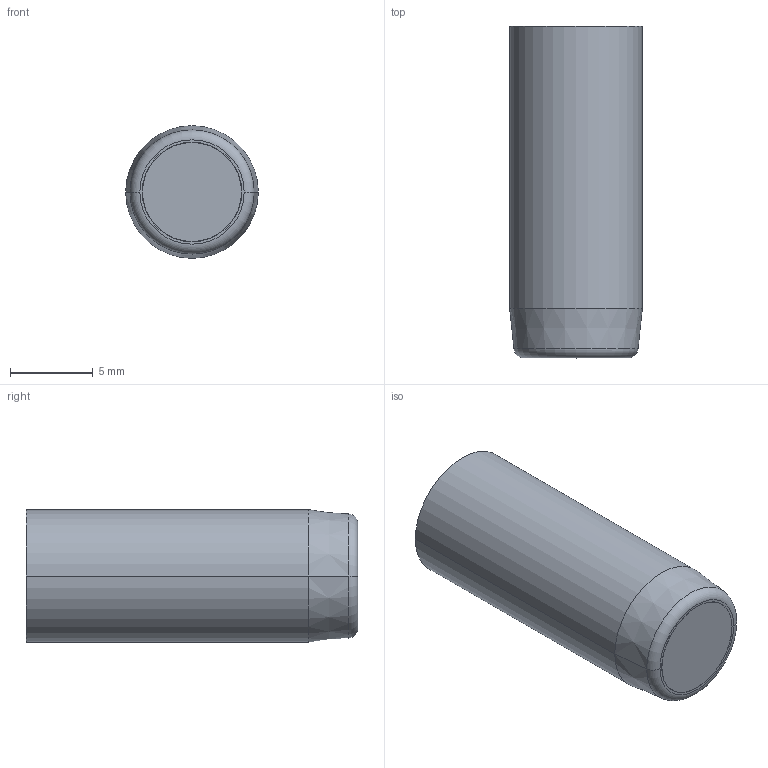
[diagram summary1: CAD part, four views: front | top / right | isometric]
STEP (ISO 10303-21) file: header records copied from the file, then geometry measured from it (millimetres).
FILE_DESCRIPTION (( 'STEP AP214' ), '1' );
FILE_NAME ('FA 084712-20.STEP', '2013-10-01T09:20:54', ( '' ), ( '' ), 'SwSTEP 2.0', 'SolidWorks 2011', '' );
FILE_SCHEMA (( 'AUTOMOTIVE_DESIGN' ));
Length unit declared in the file: millimetre
Products named in the file (6): 9FA 084712; FA 084700-2 comprimido; FA 084712-20; IA 471720; FA 084700-3; FA 084700-1
Assembly tree (5 placements, depth 2):
  FA 084712-20
    FA 084700-2 comprimido
    FA 084700-3
    FA 084700-1
    IA 471720
    9FA 084712
Bounding box: 8 x 20 x 8 mm (x, y, z)
Volume: 846.6 mm3; surface area: 1514.7 mm2
Topology: 5 solids, 5 shells, 332 faces, 839 edges, 546 vertices
Faces by surface type: plane 151, cylinder 141, cone 24, torus 12, bspline 2, sphere 2
Entity records: 11703 total; most frequent: CARTESIAN_POINT 3181, DIRECTION 1811, ORIENTED_EDGE 1674, EDGE_CURVE 837, AXIS2_PLACEMENT_3D 672, VERTEX_POINT 546, VECTOR 467, LINE 467
One B-rep face of a CAD part: STEP entity #7917.
In plain terms, the planar face has unit normal (0, -1, 0).
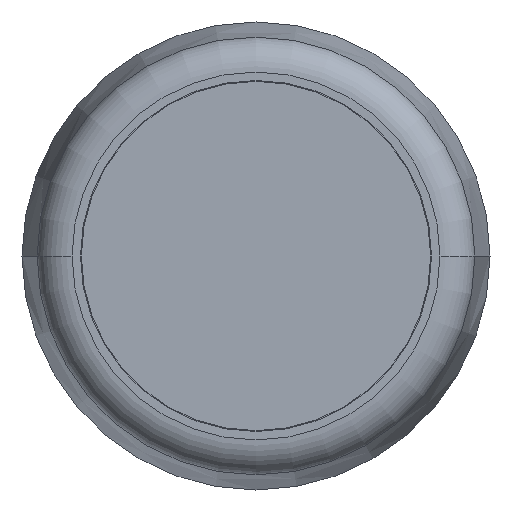
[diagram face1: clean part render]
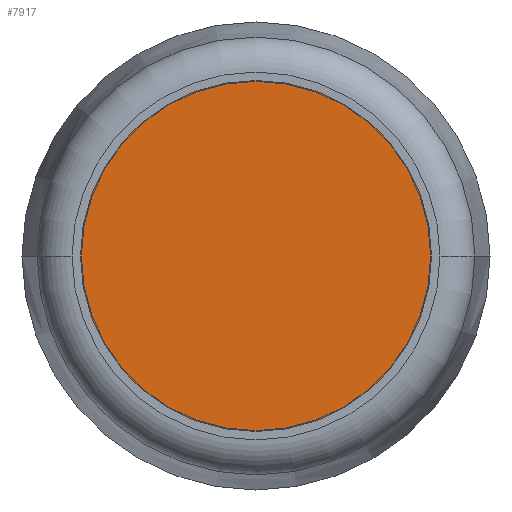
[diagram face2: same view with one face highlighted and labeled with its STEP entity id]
Its self-contained STEP definition (entity closure, numbers rounded to 3 decimals):
#1192 = EDGE_CURVE ( 'NONE', #6615, #6558, #8271, .T. ) ;
#1208 = EDGE_CURVE ( 'NONE', #6558, #6615, #11035, .T. ) ;
#1654 = CARTESIAN_POINT ( 'NONE',  ( -3.068, 0.2, -10. ) ) ;
#1659 = DIRECTION ( 'NONE',  ( 0., 1., 0. ) ) ;
#1680 = FACE_OUTER_BOUND ( 'NONE', #2554, .T. ) ;
#1686 = DIRECTION ( 'NONE',  ( 0., 0., 1. ) ) ;
#1692 = PLANE ( 'NONE',  #8713 ) ;
#2554 = EDGE_LOOP ( 'NONE', ( #10295, #10320 ) ) ;
#5687 = DIRECTION ( 'NONE',  ( 0., 0., 1. ) ) ;
#5710 = DIRECTION ( 'NONE',  ( 0., 1., 0. ) ) ;
#5712 = CARTESIAN_POINT ( 'NONE',  ( 0., 0.2, 0. ) ) ;
#5772 = CARTESIAN_POINT ( 'NONE',  ( 0., 0.2, 0. ) ) ;
#5779 = DIRECTION ( 'NONE',  ( 0., 0., 1. ) ) ;
#5810 = DIRECTION ( 'NONE',  ( 0., 1., 0. ) ) ;
#5930 = CARTESIAN_POINT ( 'NONE',  ( 0., 0.2, 3. ) ) ;
#6026 = CARTESIAN_POINT ( 'NONE',  ( 0., 0.2, -3. ) ) ;
#6558 = VERTEX_POINT ( 'NONE', #5930 ) ;
#6615 = VERTEX_POINT ( 'NONE', #6026 ) ;
#7917 = ADVANCED_FACE ( 'NONE', ( #1680 ), #1692, .F. ) ;
#8271 = CIRCLE ( 'NONE', #8276, 3. ) ;
#8276 = AXIS2_PLACEMENT_3D ( 'NONE', #5712, #5710, #5687 ) ;
#8713 = AXIS2_PLACEMENT_3D ( 'NONE', #1654, #1659, #1686 ) ;
#10295 = ORIENTED_EDGE ( 'NONE', *, *, #1208, .F. ) ;
#10320 = ORIENTED_EDGE ( 'NONE', *, *, #1192, .F. ) ;
#11028 = AXIS2_PLACEMENT_3D ( 'NONE', #5772, #5810, #5779 ) ;
#11035 = CIRCLE ( 'NONE', #11028, 3. ) ;
